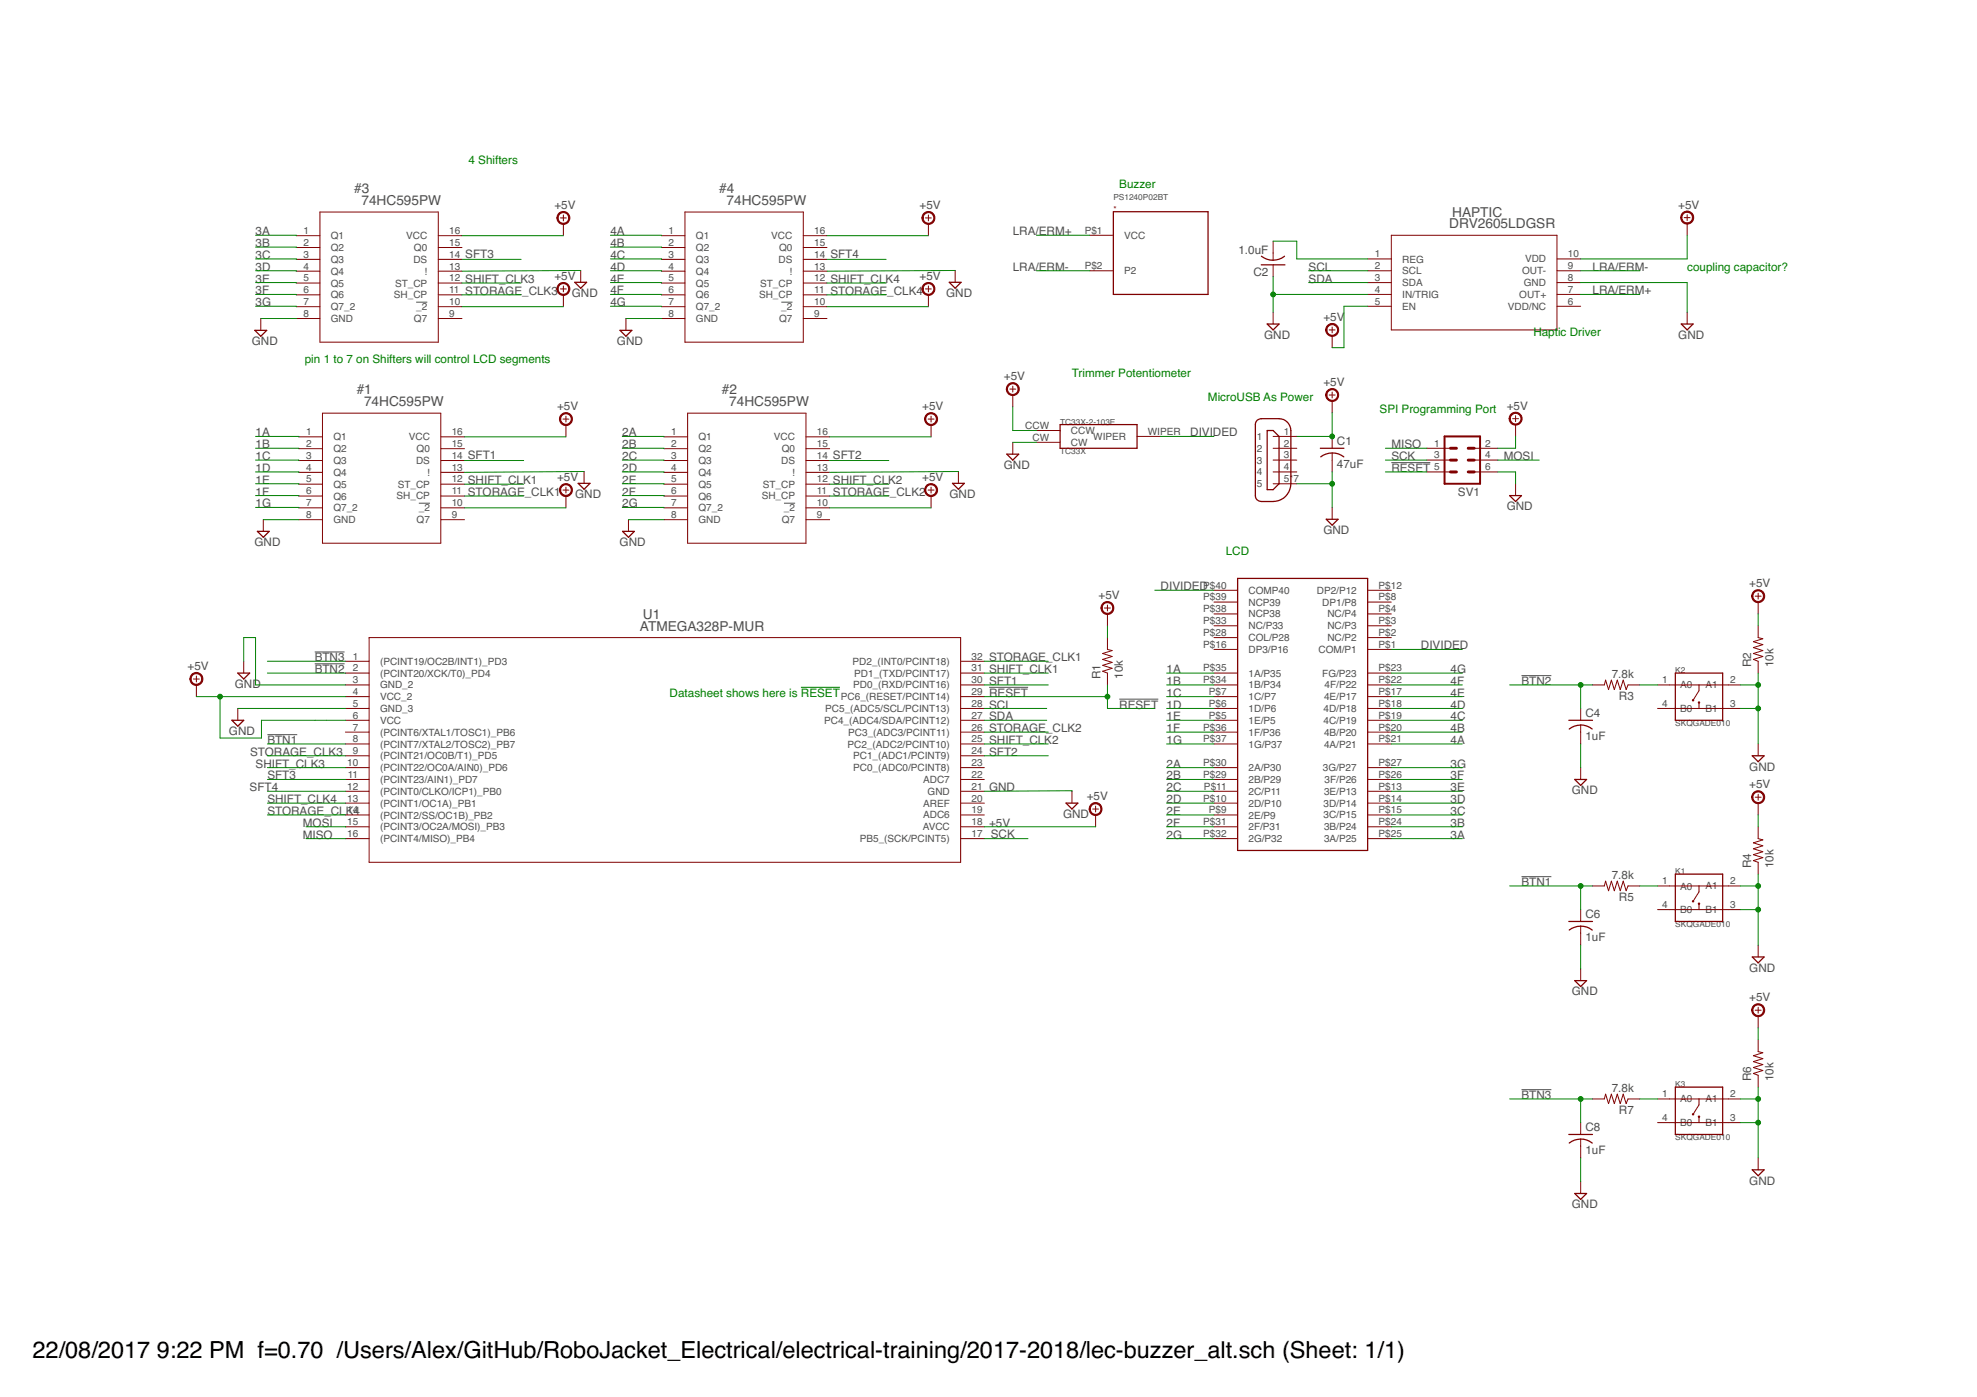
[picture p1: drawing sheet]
<svg xmlns="http://www.w3.org/2000/svg" width="297mm" height="210mm" viewBox="0 0 297 210" stroke-linecap="round" stroke-linejoin="round" font-family="sans-serif">
<defs><g id="words">
<g font-size="3.5">
<text x="4.9" y="204">22/08/2017</text>
<text x="23.6" y="204">9:22 PM f=0.70 /Users/Alex/GitHub/RoboJacket_Electrical/electrical-training/2017-2018/lec-buzzer_alt.sch (Sheet: 1/1)</text>
</g>
<g font-size="2.1" fill="#505050">
<text x="53.2" y="29">#3</text>
<text x="108.1" y="29">#4</text>
<text x="54.3" y="30.8">74HC595PW</text>
<text x="109.2" y="30.8">74HC595PW</text>
<text x="217.7" y="34.3">DRV2605LDGSR</text>
<text x="218.2" y="32.5">HAPTIC</text>
<text x="53.6" y="59.3">#1</text>
<text x="108.5" y="59.3">#2</text>
<text x="54.7" y="61">74HC595PW</text>
<text x="109.6" y="61">74HC595PW</text>
<text x="96.2" y="94.7">ATMEGA328P-MUR</text>
<text x="96.6" y="93">U1</text>
</g>
<g font-size="1.8" fill="#008000">
<text x="70.4" y="24.7">4 Shifters</text>
<text x="168.2" y="28.2">Buzzer</text>
<text x="253.5" y="40.7">coupling capacitor?</text>
<text x="230.4" y="50.5">Haptic Driver</text>
<text x="45.8" y="54.6">pin 1 to 7 on Shifters will control LCD segments</text>
<text x="161.1" y="56.7">Trimmer Potentiometer</text>
<text x="181.5" y="60.2">MicroUSB As Power</text>
<text x="207.3" y="62">SPI Programming Port</text>
<text x="184.2" y="83.3">LCD</text>
<text x="100.6" y="104.7">Datasheet shows here is RESET</text>
</g>
<g font-size="1.8" fill="#505050">
<text x="38.4" y="35.4">3A</text>
<text x="83.3" y="31.4">+5V</text>
<text x="91.7" y="35.4">4A</text>
<text x="138.2" y="31.4">+5V</text>
<text x="152.2" y="35.4">LRA/ERM+</text>
<text x="252.2" y="31.4">+5V</text>
<text x="38.4" y="37.1">3B</text>
<text x="38.4" y="38.9">3C</text>
<text x="38.4" y="40.7">3D</text>
<text x="69.9" y="38.7">SFT3</text>
<text x="91.7" y="37.1">4B</text>
<text x="91.7" y="38.9">4C</text>
<text x="91.7" y="40.7">4D</text>
<text x="124.8" y="38.7">SFT4</text>
<text x="152.2" y="40.7">LRA/ERM-</text>
<text x="186.1" y="38.1">1.0uF</text>
<text x="188.3" y="41.5">C2</text>
<text x="196.6" y="40.7">SCL</text>
<text x="239.3" y="40.7">LRA/ERM-</text>
<text x="38.4" y="42.5">3E</text>
<text x="38.4" y="44.2">3F</text>
<text x="38.4" y="46">3G</text>
<text x="69.9" y="44.3">STORAGE_CLK3</text>
<text x="69.9" y="42.6">SHIFT_CLK3</text>
<text x="83.3" y="42.1">+5V</text>
<text x="85.9" y="44.6">GND</text>
<text x="91.7" y="42.5">4E</text>
<text x="91.7" y="44.2">4F</text>
<text x="91.7" y="46">4G</text>
<text x="124.8" y="42.6">SHIFT_CLK4</text>
<text x="124.8" y="44.3">STORAGE_CLK4</text>
<text x="138.2" y="42.1">+5V</text>
<text x="142.2" y="44.6">GND</text>
<text x="196.6" y="42.5">SDA</text>
<text x="239.3" y="44.2">LRA/ERM+</text>
<text x="37.8" y="51.9">GND</text>
<text x="92.7" y="51.9">GND</text>
<text x="189.9" y="50.9">GND</text>
<text x="198.8" y="48.2">+5V</text>
<text x="252.2" y="50.9">GND</text>
<text x="150.8" y="57.1">+5V</text>
<text x="198.8" y="58">+5V</text>
<text x="38.4" y="65.6">1A</text>
<text x="83.7" y="61.6">+5V</text>
<text x="93.5" y="65.6">2A</text>
<text x="138.6" y="61.6">+5V</text>
<text x="178.8" y="65.6">DIVIDED</text>
<text x="226.4" y="61.6">+5V</text>
<text x="38.4" y="67.4">1B</text>
<text x="38.4" y="69.1">1C</text>
<text x="38.4" y="70.9">1D</text>
<text x="70.3" y="68.9">SFT1</text>
<text x="93.5" y="67.4">2B</text>
<text x="93.5" y="69.1">2C</text>
<text x="93.5" y="70.9">2D</text>
<text x="125.2" y="68.9">SFT2</text>
<text x="150.8" y="70.5">GND</text>
<text x="200.9" y="70.3">47uF</text>
<text x="200.9" y="66.9">C1</text>
<text x="209.1" y="67.4">MISO</text>
<text x="209.1" y="69.1">SCK</text>
<text x="209.1" y="70.9">RESET</text>
<text x="225.9" y="69.1">MOSI</text>
<text x="38.4" y="72.7">1E</text>
<text x="38.4" y="74.5">1F</text>
<text x="38.4" y="76.2">1G</text>
<text x="70.3" y="72.8">SHIFT_CLK1</text>
<text x="70.3" y="74.5">STORAGE_CLK1</text>
<text x="83.7" y="72.3">+5V</text>
<text x="86.4" y="74.9">GND</text>
<text x="93.5" y="72.7">2E</text>
<text x="93.5" y="74.5">2F</text>
<text x="93.5" y="76.2">2G</text>
<text x="125.2" y="74.5">STORAGE_CLK2</text>
<text x="125.2" y="72.8">SHIFT_CLK2</text>
<text x="138.6" y="72.3">+5V</text>
<text x="142.7" y="74.9">GND</text>
<text x="219.1" y="74.5">SV1</text>
<text x="226.4" y="76.7">GND</text>
<text x="38.2" y="82.1">GND</text>
<text x="93.1" y="82.1">GND</text>
<text x="198.8" y="80.2">GND</text>
<text x="174.4" y="88.7">DIVIDED</text>
<text x="262.8" y="88.2">+5V</text>
<text x="165.1" y="90">+5V</text>
<text x="28.2" y="100.7">+5V</text>
<text x="47.3" y="99.3">BTN3</text>
<text x="47.3" y="101.1">BTN2</text>
<text x="148.6" y="101.1">SHIFT_CLK1</text>
<text x="148.6" y="99.3">STORAGE_CLK1</text>
<text x="175.3" y="101.1">1A</text>
<text x="213.5" y="97.6">DIVIDED</text>
<text x="217.9" y="101.1">4G</text>
<text x="242.2" y="101.8">7.8k</text>
<text x="263.1" y="100.2" transform="rotate(-90 263.1 100.2)">R2</text>
<text x="266.5" y="100.2" transform="rotate(-90 266.5 100.2)">10k</text>
<text x="35.3" y="103.3">GND</text>
<text x="148.6" y="102.9">SFT1</text>
<text x="148.6" y="104.7">RESET</text>
<text x="148.6" y="106.5">SCL</text>
<text x="165.3" y="102" transform="rotate(-90 165.3 102)">R1</text>
<text x="168.2" y="106.5">RESET</text>
<text x="168.7" y="102" transform="rotate(-90 168.7 102)">10k</text>
<text x="175.3" y="102.9">1B</text>
<text x="175.3" y="104.7">1C</text>
<text x="175.3" y="106.5">1D</text>
<text x="217.9" y="106.5">4D</text>
<text x="217.9" y="104.7">4E</text>
<text x="217.9" y="102.9">4F</text>
<text x="228.6" y="102.9">BTN2</text>
<text x="238.2" y="107.8">C4</text>
<text x="243.2" y="105.2">R3</text>
<text x="34.4" y="110.5">GND</text>
<text x="37.6" y="113.6">STORAGE_CLK3</text>
<text x="40.2" y="111.8">BTN1</text>
<text x="148.6" y="113.6">SFT2</text>
<text x="148.6" y="108.2">SDA</text>
<text x="148.6" y="110">STORAGE_CLK2</text>
<text x="148.6" y="111.8">SHIFT_CLK2</text>
<text x="175.3" y="108.2">1E</text>
<text x="175.3" y="110">1F</text>
<text x="175.3" y="111.8">1G</text>
<text x="217.9" y="111.8">4A</text>
<text x="217.9" y="110">4B</text>
<text x="217.9" y="108.2">4C</text>
<text x="238.2" y="111.2">1uF</text>
<text x="37.5" y="118.9">SFT4</text>
<text x="38.4" y="115.3">SHIFT_CLK3</text>
<text x="40.2" y="117.1">SFT3</text>
<text x="148.6" y="118.9">GND</text>
<text x="175.3" y="115.3">2A</text>
<text x="175.3" y="117.1">2B</text>
<text x="175.3" y="118.9">2C</text>
<text x="217.9" y="118.9">3E</text>
<text x="217.9" y="117.1">3F</text>
<text x="217.9" y="115.3">3G</text>
<text x="236.2" y="119.3">GND</text>
<text x="262.8" y="115.8">GND</text>
<text x="262.8" y="118.5">+5V</text>
<text x="40.2" y="120.7">SHIFT_CLK4</text>
<text x="40.2" y="122.5">STORAGE_CLK4</text>
<text x="45.5" y="124.2">MOSI</text>
<text x="148.6" y="124.2">+5V</text>
<text x="148.9" y="125.9">SCK</text>
<text x="159.7" y="122.9">GND</text>
<text x="163.3" y="120.2">+5V</text>
<text x="175.3" y="120.7">2D</text>
<text x="175.3" y="122.5">2E</text>
<text x="175.3" y="124.2">2F</text>
<text x="217.9" y="124.2">3B</text>
<text x="217.9" y="122.5">3C</text>
<text x="217.9" y="120.7">3D</text>
<text x="45.5" y="126">MISO</text>
<text x="175.3" y="126">2G</text>
<text x="217.9" y="126">3A</text>
<text x="263.1" y="130.5" transform="rotate(-90 263.1 130.5)">R4</text>
<text x="266.5" y="130.5" transform="rotate(-90 266.5 130.5)">10k</text>
<text x="228.6" y="133.1">BTN1</text>
<text x="242.2" y="132.1">7.8k</text>
<text x="243.2" y="135.4">R5</text>
<text x="238.2" y="141.4">1uF</text>
<text x="238.2" y="138">C6</text>
<text x="236.2" y="149.6">GND</text>
<text x="262.8" y="146">GND</text>
<text x="262.8" y="150.4">+5V</text>
<text x="228.6" y="165.1">BTN3</text>
<text x="242.2" y="164.1">7.8k</text>
<text x="243.2" y="167.4">R7</text>
<text x="263.1" y="162.4" transform="rotate(-90 263.1 162.4)">R6</text>
<text x="266.5" y="162.4" transform="rotate(-90 266.5 162.4)">10k</text>
<text x="238.2" y="173.4">1uF</text>
<text x="238.2" y="170">C8</text>
<text x="262.8" y="178">GND</text>
<text x="236.2" y="181.6">GND</text>
</g>
<g font-size="1.5" fill="#505050">
<text x="45.6" y="35.2">1</text>
<text x="49.7" y="35.9">Q1</text>
<text x="61" y="35.9">VCC</text>
<text x="67.5" y="35.2">16</text>
<text x="100.5" y="35.2">1</text>
<text x="104.6" y="35.9">Q1</text>
<text x="115.9" y="35.9">VCC</text>
<text x="122.3" y="35.2">16</text>
<text x="163" y="35.1">P$1</text>
<text x="168.9" y="35.9">VCC</text>
<text x="45.6" y="36.9">2</text>
<text x="45.6" y="38.7">3</text>
<text x="45.6" y="40.5">4</text>
<text x="49.7" y="37.7">Q2</text>
<text x="49.7" y="39.5">Q3</text>
<text x="49.7" y="41.3">Q4</text>
<text x="62.1" y="39.5">DS</text>
<text x="62.2" y="37.7">Q0</text>
<text x="63.8" y="41.3">!</text>
<text x="67.5" y="40.5">13</text>
<text x="67.5" y="38.7">14</text>
<text x="67.5" y="36.9">15</text>
<text x="100.5" y="36.9">2</text>
<text x="100.5" y="38.7">3</text>
<text x="100.5" y="40.5">4</text>
<text x="104.6" y="37.7">Q2</text>
<text x="104.6" y="39.5">Q3</text>
<text x="104.6" y="41.3">Q4</text>
<text x="117" y="39.5">DS</text>
<text x="117.1" y="37.7">Q0</text>
<text x="118.6" y="41.3">!</text>
<text x="122.3" y="40.5">13</text>
<text x="122.3" y="38.7">14</text>
<text x="122.3" y="36.9">15</text>
<text x="163" y="40.4">P$2</text>
<text x="168.9" y="41.2">P2</text>
<text x="206.6" y="38.7">1</text>
<text x="206.6" y="40.4">2</text>
<text x="210.7" y="39.4">REG</text>
<text x="210.7" y="41.2">SCL</text>
<text x="228.7" y="41.2">OUT-</text>
<text x="229.1" y="39.4">VDD</text>
<text x="235.6" y="40.4">9</text>
<text x="235.6" y="38.7">10</text>
<text x="45.6" y="42.3">5</text>
<text x="45.6" y="44.1">6</text>
<text x="45.6" y="45.8">7</text>
<text x="45.6" y="47.6">8</text>
<text x="49.7" y="43.1">Q5</text>
<text x="49.7" y="44.8">Q6</text>
<text x="49.7" y="46.6">Q7_2</text>
<text x="59.2" y="44.8">SH_CP</text>
<text x="59.4" y="43">ST_CP</text>
<text x="62.5" y="46.6">_2</text>
<text x="67.5" y="47.6">9</text>
<text x="67.5" y="45.8">10</text>
<text x="67.5" y="44.1">11</text>
<text x="67.5" y="42.3">12</text>
<text x="100.5" y="42.3">5</text>
<text x="100.5" y="44.1">6</text>
<text x="100.5" y="45.8">7</text>
<text x="100.5" y="47.6">8</text>
<text x="104.6" y="43.1">Q5</text>
<text x="104.6" y="44.8">Q6</text>
<text x="104.6" y="46.6">Q7_2</text>
<text x="114" y="44.8">SH_CP</text>
<text x="114.2" y="43">ST_CP</text>
<text x="117.4" y="46.6">_2</text>
<text x="122.3" y="47.6">9</text>
<text x="122.3" y="45.8">10</text>
<text x="122.3" y="44.1">11</text>
<text x="122.3" y="42.3">12</text>
<text x="206.6" y="42.2">3</text>
<text x="206.6" y="44">4</text>
<text x="206.6" y="45.8">5</text>
<text x="210.7" y="43">SDA</text>
<text x="210.7" y="44.8">IN/TRIG</text>
<text x="210.7" y="46.6">EN</text>
<text x="226.5" y="46.5">VDD/NC</text>
<text x="228.3" y="44.8">OUT+</text>
<text x="229" y="43">GND</text>
<text x="235.6" y="45.8">6</text>
<text x="235.6" y="44">7</text>
<text x="235.6" y="42.2">8</text>
<text x="49.7" y="48.4">GND</text>
<text x="62.2" y="48.4">Q7</text>
<text x="104.6" y="48.4">GND</text>
<text x="117.1" y="48.4">Q7</text>
<text x="46" y="65.4">1</text>
<text x="67.9" y="65.4">16</text>
<text x="100.9" y="65.4">1</text>
<text x="122.7" y="65.4">16</text>
<text x="154" y="64.4">CCW</text>
<text x="160.9" y="65.2">CCW</text>
<text x="172.5" y="65.3">WIPER</text>
<text x="192.9" y="65.3">1</text>
<text x="46" y="67.2">2</text>
<text x="46" y="68.9">3</text>
<text x="46" y="70.7">4</text>
<text x="50.1" y="66.2">Q1</text>
<text x="50.1" y="67.9">Q2</text>
<text x="50.1" y="69.7">Q3</text>
<text x="50.1" y="71.5">Q4</text>
<text x="61.4" y="66.2">VCC</text>
<text x="62.5" y="69.7">DS</text>
<text x="62.6" y="67.9">Q0</text>
<text x="64.2" y="71.5">!</text>
<text x="67.9" y="70.7">13</text>
<text x="67.9" y="68.9">14</text>
<text x="67.9" y="67.2">15</text>
<text x="100.9" y="67.2">2</text>
<text x="100.9" y="68.9">3</text>
<text x="100.9" y="70.7">4</text>
<text x="105" y="66.2">Q1</text>
<text x="105" y="67.9">Q2</text>
<text x="105" y="69.7">Q3</text>
<text x="105" y="71.5">Q4</text>
<text x="116.3" y="66.2">VCC</text>
<text x="117.4" y="69.7">DS</text>
<text x="117.4" y="67.9">Q0</text>
<text x="119" y="71.5">!</text>
<text x="122.7" y="70.7">13</text>
<text x="122.7" y="68.9">14</text>
<text x="122.7" y="67.2">15</text>
<text x="155.1" y="66.2">CW</text>
<text x="160.9" y="67">CW</text>
<text x="164.3" y="66.1">WIPER</text>
<text x="188.8" y="66.1">1</text>
<text x="188.8" y="67.9">2</text>
<text x="188.8" y="69.7">3</text>
<text x="188.8" y="71.4">4</text>
<text x="192.9" y="67.1">2</text>
<text x="192.9" y="68.9">3</text>
<text x="192.9" y="70.7">4</text>
<text x="215.5" y="67.1">1</text>
<text x="215.5" y="68.9">3</text>
<text x="215.5" y="70.7">5</text>
<text x="223.1" y="67.1">2</text>
<text x="223.1" y="68.9">4</text>
<text x="223.1" y="70.7">6</text>
<text x="46" y="72.5">5</text>
<text x="46" y="74.3">6</text>
<text x="46" y="76">7</text>
<text x="46" y="77.8">8</text>
<text x="50.1" y="73.3">Q5</text>
<text x="50.1" y="75.1">Q6</text>
<text x="50.1" y="76.8">Q7_2</text>
<text x="59.6" y="75">SH_CP</text>
<text x="59.8" y="73.3">ST_CP</text>
<text x="62.9" y="76.8">_2</text>
<text x="67.9" y="77.8">9</text>
<text x="67.9" y="76">10</text>
<text x="67.9" y="74.3">11</text>
<text x="67.9" y="72.5">12</text>
<text x="100.9" y="72.5">5</text>
<text x="100.9" y="74.3">6</text>
<text x="100.9" y="76">7</text>
<text x="100.9" y="77.8">8</text>
<text x="105" y="73.3">Q5</text>
<text x="105" y="75.1">Q6</text>
<text x="105" y="76.8">Q7_2</text>
<text x="114.4" y="75">SH_CP</text>
<text x="114.6" y="73.3">ST_CP</text>
<text x="117.8" y="76.8">_2</text>
<text x="122.7" y="77.8">9</text>
<text x="122.7" y="76">10</text>
<text x="122.7" y="74.3">11</text>
<text x="122.7" y="72.5">12</text>
<text x="188.8" y="73.2">5</text>
<text x="192.9" y="72.4">5*</text>
<text x="194.3" y="72.4">7</text>
<text x="50.1" y="78.6">GND</text>
<text x="62.6" y="78.6">Q7</text>
<text x="105" y="78.6">GND</text>
<text x="117.4" y="78.6">Q7</text>
<text x="180.8" y="88.4">P$40</text>
<text x="187.6" y="89.2">COMP40</text>
<text x="197.8" y="89.2">DP2/P12</text>
<text x="207.1" y="88.4">P$12</text>
<text x="180.8" y="90.2">P$39</text>
<text x="180.8" y="92">P$38</text>
<text x="180.8" y="93.8">P$33</text>
<text x="180.8" y="95.5">P$28</text>
<text x="187.6" y="91">NCP39</text>
<text x="187.6" y="92.8">NCP38</text>
<text x="187.6" y="94.5">NC/P33</text>
<text x="198.7" y="91">DP1/P8</text>
<text x="199.4" y="94.5">NC/P3</text>
<text x="199.4" y="92.8">NC/P4</text>
<text x="207.1" y="95.5">P$2</text>
<text x="207.1" y="93.8">P$3</text>
<text x="207.1" y="92">P$4</text>
<text x="207.1" y="90.2">P$8</text>
<text x="53" y="99.1">1</text>
<text x="53" y="100.9">2</text>
<text x="57.1" y="99.9">(PCINT19/OC2B/INT1)_PD3</text>
<text x="57.1" y="101.7">(PCINT20/XCK/T0)_PD4</text>
<text x="128.1" y="99.9">PD2_(INT0/PCINT18)</text>
<text x="128.4" y="101.6">PD1_(TXD/PCINT17)</text>
<text x="146" y="100.9">31</text>
<text x="146" y="99.1">32</text>
<text x="180.8" y="100.9">P$35</text>
<text x="180.8" y="97.3">P$16</text>
<text x="187.6" y="101.7">1A/P35</text>
<text x="187.6" y="96.3">COL/P28</text>
<text x="187.6" y="98.1">DP3/P16</text>
<text x="198.1" y="98.1">COM/P1</text>
<text x="198.7" y="101.6">FG/P23</text>
<text x="199.4" y="96.3">NC/P2</text>
<text x="207.1" y="100.9">P$23</text>
<text x="207.1" y="97.3">P$1</text>
<text x="53" y="102.7">3</text>
<text x="53" y="104.4">4</text>
<text x="53" y="106.2">5</text>
<text x="53" y="108">6</text>
<text x="57.1" y="103.4">GND_2</text>
<text x="57.1" y="105.2">VCC_2</text>
<text x="57.1" y="107">GND_3</text>
<text x="124" y="107">PC5_(ADC5/SCL/PCINT13)</text>
<text x="126.3" y="105.2">PC6_(RESET/PCINT14)</text>
<text x="128.2" y="103.4">PD0_(RXD/PCINT16)</text>
<text x="146" y="108">27</text>
<text x="146" y="106.2">28</text>
<text x="146" y="104.4">29</text>
<text x="146" y="102.7">30</text>
<text x="180.8" y="102.7">P$34</text>
<text x="181.6" y="104.4">P$7</text>
<text x="181.6" y="106.2">P$6</text>
<text x="181.6" y="108">P$5</text>
<text x="187.6" y="103.4">1B/P34</text>
<text x="187.6" y="105.2">1C/P7</text>
<text x="187.6" y="107">1D/P6</text>
<text x="198.8" y="107">4D/P18</text>
<text x="198.9" y="105.2">4E/P17</text>
<text x="199" y="103.4">4F/P22</text>
<text x="207.1" y="108">P$19</text>
<text x="207.1" y="106.2">P$18</text>
<text x="207.1" y="104.4">P$17</text>
<text x="207.1" y="102.7">P$22</text>
<text x="249.8" y="102.7">1</text>
<text x="249.8" y="106.2">4</text>
<text x="252.5" y="103.4">A0</text>
<text x="252.5" y="107">B0</text>
<text x="256.2" y="103.4">A1</text>
<text x="256.2" y="107">B1</text>
<text x="260" y="102.7">2</text>
<text x="260" y="106.2">3</text>
<text x="53" y="109.8">7</text>
<text x="53" y="111.5">8</text>
<text x="53" y="113.3">9</text>
<text x="57.1" y="108.8">VCC</text>
<text x="57.1" y="110.5">(PCINT6/XTAL1/TOSC1)_PB6</text>
<text x="57.1" y="112.3">(PCINT7/XTAL2/TOSC2)_PB7</text>
<text x="123.8" y="108.8">PC4_(ADC4/SDA/PCINT12)</text>
<text x="127.3" y="112.3">PC2_(ADC2/PCINT10)</text>
<text x="127.4" y="110.5">PC3_(ADC3/PCINT11)</text>
<text x="146" y="113.3">24</text>
<text x="146" y="111.5">25</text>
<text x="146" y="109.8">26</text>
<text x="180.8" y="109.8">P$36</text>
<text x="180.8" y="111.5">P$37</text>
<text x="187.6" y="108.8">1E/P5</text>
<text x="187.6" y="110.5">1F/P36</text>
<text x="187.6" y="112.3">1G/P37</text>
<text x="198.8" y="108.8">4C/P19</text>
<text x="198.9" y="112.3">4A/P21</text>
<text x="198.9" y="110.5">4B/P20</text>
<text x="207.1" y="111.5">P$21</text>
<text x="207.1" y="109.8">P$20</text>
<text x="52.2" y="115.1">10</text>
<text x="52.2" y="118.7">12</text>
<text x="52.3" y="116.9">11</text>
<text x="57.1" y="114.1">(PCINT21/OC0B/T1)_PD5</text>
<text x="57.1" y="115.9">(PCINT22/OC0A/AIN0)_PD6</text>
<text x="57.1" y="117.7">(PCINT23/AIN1)_PD7</text>
<text x="57.1" y="119.4">(PCINT0/CLKO/ICP1)_PB0</text>
<text x="128.2" y="115.9">PC0_(ADC0/PCINT8)</text>
<text x="128.2" y="114.1">PC1_(ADC1/PCINT9)</text>
<text x="138.7" y="117.6">ADC7</text>
<text x="139.4" y="119.4">GND</text>
<text x="146" y="118.7">21</text>
<text x="146" y="116.9">22</text>
<text x="146" y="115.1">23</text>
<text x="180.8" y="115.1">P$30</text>
<text x="180.8" y="116.9">P$29</text>
<text x="180.9" y="118.7">P$11</text>
<text x="187.6" y="115.9">2A/P30</text>
<text x="187.6" y="117.7">2B/P29</text>
<text x="187.6" y="119.4">2C/P11</text>
<text x="198.8" y="115.9">3G/P27</text>
<text x="198.9" y="119.4">3E/P13</text>
<text x="199" y="117.6">3F/P26</text>
<text x="207.1" y="118.7">P$13</text>
<text x="207.1" y="116.9">P$26</text>
<text x="207.1" y="115.1">P$27</text>
<text x="52.2" y="120.4">13</text>
<text x="52.2" y="122.2">14</text>
<text x="52.2" y="124">15</text>
<text x="52.2" y="125.8">16</text>
<text x="57.1" y="121.2">(PCINT1/OC1A)_PB1</text>
<text x="57.1" y="123">(PCINT2/SS/OC1B)_PB2</text>
<text x="57.1" y="124.8">(PCINT3/OC2A/MOSI)_PB3</text>
<text x="138.6" y="124.8">AVCC</text>
<text x="138.7" y="123">ADC6</text>
<text x="138.7" y="121.2">AREF</text>
<text x="146" y="125.8">17</text>
<text x="146" y="124">18</text>
<text x="146" y="122.2">19</text>
<text x="146" y="120.4">20</text>
<text x="180.8" y="120.4">P$10</text>
<text x="180.8" y="124">P$31</text>
<text x="180.8" y="125.8">P$32</text>
<text x="181.6" y="122.2">P$9</text>
<text x="187.6" y="121.2">2D/P10</text>
<text x="187.6" y="123">2E/P9</text>
<text x="187.6" y="124.8">2F/P31</text>
<text x="198.8" y="123">3C/P15</text>
<text x="198.8" y="121.2">3D/P14</text>
<text x="198.9" y="124.8">3B/P24</text>
<text x="207.1" y="125.8">P$25</text>
<text x="207.1" y="124">P$24</text>
<text x="207.1" y="122.2">P$15</text>
<text x="207.1" y="120.4">P$14</text>
<text x="57.1" y="126.5">(PCINT4/MISO)_PB4</text>
<text x="129.2" y="126.5">PB5_(SCK/PCINT5)</text>
<text x="187.6" y="126.5">2G/P32</text>
<text x="198.9" y="126.5">3A/P25</text>
<text x="249.8" y="132.9">1</text>
<text x="249.8" y="136.4">4</text>
<text x="252.5" y="133.7">A0</text>
<text x="252.5" y="137.2">B0</text>
<text x="256.2" y="133.6">A1</text>
<text x="256.2" y="137.2">B1</text>
<text x="260" y="132.9">2</text>
<text x="260" y="136.4">3</text>
<text x="249.8" y="164.9">1</text>
<text x="252.5" y="165.6">A0</text>
<text x="256.2" y="165.6">A1</text>
<text x="260" y="164.9">2</text>
<text x="249.8" y="168.4">4</text>
<text x="252.5" y="169.2">B0</text>
<text x="256.2" y="169.2">B1</text>
<text x="260" y="168.4">3</text>
</g>
<g font-size="1.2" fill="#505050">
<text x="167.3" y="30">PS1240P02BT</text>
<text x="159.3" y="63.8">TC33X-2-103E</text>
<text x="159.3" y="68.2">TC33X</text>
<text x="251.7" y="101.1">K2</text>
<text x="251.7" y="109.1">SKQGADE010</text>
<text x="251.7" y="131.3">K1</text>
<text x="251.7" y="139.3">SKQGADE010</text>
<text x="251.7" y="163.3">K3</text>
<text x="251.7" y="171.3">SKQGADE010</text>
</g>
<text font-size="1.2" fill="#800000" x="167.3" y="31.8">*</text>
</g></defs>
<g fill="none" stroke="#505050" stroke-width=".15">
<path d="M62.5 45.4h1.7M117.4 45.4h1.7M62.9 75.6h1.7M117.8 75.6h1.7M209 69.5h5.9M47.3 98h4.5M47.3 99.7h4.5M40.2 110.4h4.5M148.6 103.3h5.9M168.2 105.1h5.8M228.6 101.5h4.5M228.6 131.7h4.5"/>
<path d="M228.6 163.7h4.5"/>
</g>
<g fill="none" stroke="#800000" stroke-width=".15">
<path d="M44.5 35.4h3.6M44.5 37.2h3.6M44.5 39h3.6M48.1 31.9h17.7v19.5h-17.7zM65.8 35.4h3.6M65.8 37.2h3.6M65.8 39h3.6M84.2 32.7h.9M84.6 32.3v.9M84.6 33.6v1.8M99.4 35.4h3.5M99.4 37.2h3.5"/>
<path d="M99.4 39h3.5M102.9 31.9h17.8v19.5h-17.8zM120.7 35.4h3.5M120.7 37.2h3.5M120.7 39h3.5M139 32.7h.9M139.5 32.3v.9M139.5 33.6v1.8M163.7 35.3h3.6M191.3 36.2v2.9M191.3 39.8v1.8M205.5 38.9h3.5"/>
<path d="M209 35.3h24.9v14.3h-24.9zM233.9 38.9h3.6M253 32.7h.9M253.5 32.3v.8M253.5 33.6v1.7M39.2 47.9v1.7M44.5 40.7h3.6M44.5 42.5h3.6M44.5 44.3h3.6M44.5 46.1h3.6M44.5 47.9h3.6M65.8 40.7h3.6"/>
<path d="M65.8 42.5h3.6M65.8 44.3h3.6M65.8 46.1h3.6M65.8 47.9h3.6M84.2 43.4h.9M84.6 43v.9M84.6 44.3v1.8M87.2 40.6v1.8M94 47.9v1.7M99.4 40.7h3.5M99.4 42.5h3.5M99.4 44.3h3.5"/>
<path d="M99.4 46.1h3.5M99.4 47.9h3.5M120.7 40.7h3.5M120.7 42.5h3.5M120.7 44.3h3.5M120.7 46.1h3.5M120.7 47.9h3.5M139 43.4h.9M139.5 43v.9M139.5 44.3v1.8M143.5 40.6v1.8M151.7 58.5h.9"/>
<path d="M152.2 58v.9M152.2 59.4v1.7M163.7 40.7h3.6M191.3 46.9v1.8M199.7 59.4h.9M199.7 49.6h.9M200.2 49.1v.9M200.2 50.5v1.7M200.2 58.9v.9M205.5 40.7h3.5M205.5 42.5h3.5M205.5 44.2h3.5"/>
<path d="M205.5 46h3.5M233.9 40.7h3.6M233.9 42.5h3.6M233.9 44.2h3.6M233.9 46h3.6M253.5 46.9v1.8M39.6 78.1v1.7M44.9 65.6h3.6M44.9 67.4h3.6M44.9 69.2h3.6M44.9 71h3.6M44.9 72.7h3.6"/>
<path d="M44.9 74.5h3.6M44.9 76.3h3.6M44.9 78.1h3.6M48.5 62.1h17.7v19.5h-17.7zM66.2 65.6h3.6M66.2 67.4h3.6M66.2 69.2h3.6M66.2 71h3.6M66.2 72.7h3.6M66.2 74.5h3.6M66.2 76.3h3.6M66.2 78.1h3.6"/>
<path d="M84.6 63h.9M84.6 73.6h.9M85 62.5v.9M85 63.9v1.7M85 73.2v.9M85 74.5v1.8M87.8 70.8v1.8M94.4 78.1v1.7M99.8 65.6h3.5M99.8 67.4h3.5M99.8 69.2h3.5M99.8 71h3.5"/>
<path d="M99.8 72.7h3.5M99.8 74.5h3.5M99.8 76.3h3.5M99.8 78.1h3.5M103.3 62.1h17.8v19.5h-17.8zM121.1 65.6h3.6M121.1 67.4h3.6M121.1 69.2h3.6M121.1 71h3.6M121.1 72.7h3.6M121.1 74.5h3.6M121.1 76.3h3.6"/>
<path d="M121.1 78.1h3.6M139.4 63h.9M139.4 73.6h.9M139.9 62.5v.9M139.9 63.9v1.7M139.9 73.2v.9M139.9 74.5v1.8M144 70.8v1.8M152.2 66.5v1.7M155.7 64.7h3.6M155.7 66.5h3.6M170.8 65.6h3.6"/>
<path d="M191.3 65.6h3.5M191.3 67.4h3.5M191.3 69.1h3.5M191.3 70.9h3.5M191.3 72.7h3.5M200.2 60.2v1.8M200.2 65.6v1.8M200.2 68.1v2.8M200.2 76.2v1.8M214.4 67.4h3.5M214.4 69.1h3.5M214.4 70.9h3.5"/>
<path d="M221.5 67.4h3.5M221.5 69.1h3.5M221.5 70.9h3.5M227.3 62.9h.9M227.7 62.5v.9M227.7 63.8v1.8M227.7 72.7v1.8M36.6 99.4v1.7M51.9 99.4h3.6M55.5 95.8h88.8v33.8h-88.8zM144.3 99.4h3.6M165.9 91.4h.9"/>
<path d="M166.4 95.8v1.8l.7 .1-1.4 .5 1.4 .4-1.4 .5 1.4 .4-1.4 .5 1.4 .4-1.4 .5 .7 .2v1.8M166.4 90.9v.9M166.4 92.2v1.8M182.4 95.8h3.5M182.4 97.6h3.5M182.4 94h3.5M182.4 92.2h3.5M182.4 90.5h3.5M182.4 88.7h3.5M205.5 95.8h3.5M205.5 97.6h3.5M205.5 94h3.5"/>
<path d="M205.5 92.2h3.5M205.5 90.5h3.5M205.5 88.7h3.5M263.7 89.6h.9M264.2 89.1v.9M264.2 90.5v1.7M264.2 94v1.8l.7 .2-1.5 .4 1.5 .5-1.5 .4 1.5 .4-1.5 .5 1.5 .4-1.5 .5 .8 .3v1.7M29.1 102h.9M29.5 101.6v.9M29.5 102.9v1.8M35.7 106.4v1.8M51.9 101.1h3.6"/>
<path d="M51.9 102.9h3.6M51.9 104.7h3.6M51.9 106.4h3.6M51.9 108.2h3.6M51.9 110h3.6M51.9 111.8h3.6M51.9 113.6h3.6M51.9 115.3h3.6M51.9 117.1h3.6M51.9 118.9h3.6M144.3 101.1h3.6M144.3 102.9h3.6"/>
<path d="M144.3 104.7h3.6M144.3 106.4h3.6M144.3 108.2h3.6M144.3 110h3.6M144.3 111.8h3.6M144.3 113.6h3.6M144.3 115.3h3.6M144.3 117.1h3.6M144.3 118.9h3.6M161.1 118.9v1.8M182.4 101.1h3.5M182.4 102.9h3.5"/>
<path d="M182.4 104.7h3.5M182.4 106.4h3.5M182.4 108.2h3.5M182.4 110h3.5M182.4 111.8h3.5M182.4 115.3h3.5M182.4 117.1h3.5M182.4 118.9h3.5M205.5 101.1h3.5M205.5 102.9h3.5M205.5 104.7h3.5M205.5 106.4h3.5"/>
<path d="M205.5 108.2h3.5M205.5 110h3.5M205.5 111.8h3.5M205.5 115.3h3.5M205.5 117.1h3.5M205.5 118.9h3.5M237.5 106.4v1.8M237.5 108.9v2.9M237.5 115.3v1.8M239.3 102.9h1.7l.2-.7 .5 1.4 .4-1.4 .4 1.4 .5-1.4 .4 1.4 .5-1.4 .4 1.4 .3-.7h1.8M249 102.9h12.5M249 106.4h12.5"/>
<path d="M255.3 102.9v.9l-.9 1.4M255.3 105.6v.8M263.7 119.8h.9M264.2 111.8v1.8M264.2 119.3v.9M51.9 120.7h3.6M51.9 122.4h3.6M51.9 124.2h3.6M51.9 126h3.6M144.3 120.7h3.6M144.3 122.4h3.6M144.3 124.2h3.6"/>
<path d="M144.3 126h3.6M164.2 121.6h.9M164.6 121.1v.9M164.6 122.4v1.8M182.4 120.7h3.5M182.4 122.4h3.5M182.4 124.2h3.5M182.4 126h3.5M205.5 120.7h3.5M205.5 122.4h3.5M205.5 124.2h3.5M205.5 126h3.5"/>
<path d="M237.5 136.7v1.8M237.5 139.2v2.8M239.3 133.1h1.7l.2-.7 .5 1.4 .4-1.4 .4 1.4 .5-1.4 .4 1.4 .5-1.4 .4 1.4 .3-.7h1.8M249 133.1h12.5M249 136.7h12.5M255.3 133.1v.9l-.9 1.4M255.3 135.8v.9M264.2 120.7v1.7M264.2 124.2v1.8l.7 .2-1.5 .4 1.5 .5-1.5 .4 1.5 .5-1.5 .4 1.5 .5-1.5 .4 .8 .3v1.7M237.5 145.6v1.7M263.7 151.8h.9M264.2 142v1.8"/>
<path d="M264.2 151.3v.9M264.2 152.7v1.8M264.2 156.2v1.8l.7 .2-1.5 .4 1.5 .5-1.5 .4 1.5 .5-1.5 .4 1.5 .4-1.5 .5 .8 .3v1.7M237.5 168.7v1.8M237.5 171.2v2.8M237.5 177.5v1.8M239.3 165.1h1.7l.2-.7 .5 1.4 .4-1.4 .4 1.4 .5-1.4 .4 1.4 .5-1.4 .4 1.4 .3-.7h1.8M249 165.1h12.5M249 168.7h12.5M255.3 165.1v.9l-.9 1.4M255.3 167.8v.9M264.2 174v1.8"/>
</g>
<g fill="none" stroke="#800000" stroke-width=".19">
<path d="M167.3 31.8h14.2v12.4h-14.2zM189.5 39.8h3.6M189.5 38.5a2.84 2.84 0 0 0 3.5 0M38.3 49.6h1.8l-.9 .9zM86.4 42.4h1.7l-.9 .9zM93.2 49.6h1.7l-.9 .9zM142.6 42.4h1.8l-.9 .9zM190.4 48.7h1.8l-.9 .9zM252.6 48.7h1.8l-.9 .9zM38.7 79.8h1.7l-.8 .9zM86.9 72.6h1.7l-.8 .9zM93.5 79.8h1.8l-.9 .9z"/>
<path d="M143.1 72.6h1.8l-.9 .9zM151.3 68.2h1.8l-.9 .9zM159.3 63.8h11.5v3.6h-11.5zM188.9 63.2l.6-.3h2.7a1.81 1.81 0 0 1 1.8 1.8v8a2.67 2.67 0 0 1-2.7 2.7l-2-.1a.83 .83 0 0 1-.7-.8v-10.7zM190.4 64.7h.9l.9 .9v7.1l-.9 .9h-.9zM198.4 67.4h3.5M198.4 68.6a2.84 2.84 0 0 1 3.5 0M199.3 78h1.7l-.8 .9zM226.8 74.5h1.8l-.9 .9zM185.9 86.9h19.6v40.9h-19.6zM34.8 108.2h1.8l-.9 .9zM35.7 101.1h1.8l-.9 .9z"/>
<path d="M235.7 108.2h3.6M235.8 109.5a2.73 2.73 0 0 1 3.4 0M236.6 117.1h1.8l-.9 .9zM251.7 101.1h7.1v7.1h-7.1zM263.3 113.6h1.7l-.8 .8zM160.2 120.7h1.7l-.8 .9zM235.7 138.5h3.6M235.8 139.7a2.81 2.81 0 0 1 3.4 0M251.7 131.3h7.1v7.2h-7.1zM236.6 147.3h1.8l-.9 .9zM263.3 143.8h1.7l-.8 .9zM235.7 170.5h3.6"/>
<path d="M235.8 171.7a2.81 2.81 0 0 1 3.4 0M236.6 179.3h1.8l-.9 .9zM251.7 163.3h7.1v7.2h-7.1zM263.3 175.8h1.7l-.8 .9z"/>
</g>
<g fill="#800000" stroke="#800000" stroke-width=".15">
<path d="M199.3 58.8a.98 .98 0 0 1 1.6 0 .98 .98 0 0 1-.4 1.5 .98 .98 0 0 1-1.3-.9h.2a.8 .8 0 0 1 1.1-.7 .8 .8 0 0 1 .2 1.3 .8 .8 0 0 1-1.3-.4v-.2h-.2z" fill-rule="evenodd"/>
<path d="M84.4 62.2a.98 .98 0 0 1 1.5 .4 .98 .98 0 0 1-.7 1.3 .98 .98 0 0 1-1.1-.9h.1a.8 .8 0 0 1 1.2-.7 .8 .8 0 0 1 .1 1.3 .8 .8 0 0 1-1.2-.4l-.1-.2h-.1v-.3z" fill-rule="evenodd"/>
<path d="M84.4 72.9a.98 .98 0 0 1 1.5 .3 .98 .98 0 0 1-.6 1.4 .98 .98 0 0 1-1.2-1h.1a.8 .8 0 0 1 1.2-.6 .8 .8 0 0 1 .1 1.3 .8 .8 0 0 1-1.2-.4l-.1-.3h-.1v-.3z" fill-rule="evenodd"/>
<path d="M139.3 62.2a.98 .98 0 0 1 1.5 .3 .98 .98 0 0 1-.7 1.4 .98 .98 0 0 1-1.2-.9h.2a.8 .8 0 0 1 1.1-.8 .8 .8 0 0 1 .2 1.3 .8 .8 0 0 1-1.3-.3v-.2h-.2l.1-.3z" fill-rule="evenodd"/>
<path d="M139.3 72.9a.98 .98 0 0 1 1.5 .3 .98 .98 0 0 1-.7 1.4 .98 .98 0 0 1-1.2-1h.2a.8 .8 0 0 1 1.1-.7 .8 .8 0 0 1 .2 1.3 .8 .8 0 0 1-1.3-.3v-.3h-.2l.1-.3z" fill-rule="evenodd"/>
<path d="M84 32a.97 .97 0 0 1 1.5 .3 .97 .97 0 0 1-.6 1.4 .97 .97 0 0 1-1.2-1h.1a.8 .8 0 0 1 1.1-.7 .8 .8 0 0 1 .3 1.3 .8 .8 0 0 1-1.3-.3l-.1-.3h-.1l.1-.5z" fill-rule="evenodd"/>
<path d="M84 42.7a.97 .97 0 0 1 1.5 .3 .97 .97 0 0 1-.6 1.4 .97 .97 0 0 1-1.2-1h.1a.8 .8 0 0 1 1.1-.7 .8 .8 0 0 1 .3 1.3 .8 .8 0 0 1-1.3-.4l-.1-.2h-.1v-.3z" fill-rule="evenodd"/>
<path d="M138.7 32.2a.98 .98 0 0 1 1.6 0 .98 .98 0 0 1-.5 1.5 .98 .98 0 0 1-1.3-1h.2a.8 .8 0 0 1 1.2-.6 .8 .8 0 0 1 .1 1.3 .8 .8 0 0 1-1.3-.4v-.3h-.2z" fill-rule="evenodd"/>
<path d="M138.7 42.9a.98 .98 0 0 1 1.6-.1 .98 .98 0 0 1-.5 1.5 .98 .98 0 0 1-1.3-.9h.2a.8 .8 0 0 1 1.2-.7 .8 .8 0 0 1 .1 1.4 .8 .8 0 0 1-1.3-.5v-.2h-.2z" fill-rule="evenodd"/>
<path d="M164 120.8a.97 .97 0 0 1 1.5 .3 .97 .97 0 0 1-.7 1.4 .97 .97 0 0 1-1.2-.9h.2a.8 .8 0 0 1 1.1-.8 .8 .8 0 0 1 .2 1.3 .8 .8 0 0 1-1.2-.3l-.1-.2h-.2l.2-.6z" fill-rule="evenodd"/>
<path d="M165.8 90.6a.97 .97 0 0 1 1.5 .3 .97 .97 0 0 1-.7 1.4 .97 .97 0 0 1-1.2-.9h.2a.8 .8 0 0 1 1.1-.8 .8 .8 0 0 1 .2 1.3 .8 .8 0 0 1-1.3-.3v-.2h-.2l.1-.3z" fill-rule="evenodd"/>
<path d="M151.6 57.7a.98 .98 0 0 1 1.5 .3 .98 .98 0 0 1-.7 1.4 .98 .98 0 0 1-1.2-.9h.2a.8 .8 0 0 1 1.1-.8 .8 .8 0 0 1 .2 1.3 .8 .8 0 0 1-1.3-.3v-.2h-.2l.2-.6z" fill-rule="evenodd"/>
<path d="M227.1 62.1a.98 .98 0 0 1 1.5 .4 .98 .98 0 0 1-.7 1.4 .98 .98 0 0 1-1.2-1h.2a.81 .81 0 0 1 1.1-.8 .81 .81 0 0 1 .3 1.4 .81 .81 0 0 1-1.4-.4v-.2h-.2l.1-.3z" fill-rule="evenodd"/>
<path d="M199.3 49a.98 .98 0 0 1 1.6 0 .98 .98 0 0 1-.4 1.5 .98 .98 0 0 1-1.3-.9h.2a.8 .8 0 0 1 1.1-.7 .8 .8 0 0 1 .2 1.3 .8 .8 0 0 1-1.3-.4v-.2h-.2z" fill-rule="evenodd"/>
<path d="M28.9 101.2a.98 .98 0 0 1 1.5 .4 .98 .98 0 0 1-.6 1.4 .98 .98 0 0 1-1.3-1h.2a.8 .8 0 0 1 1.1-.7 .8 .8 0 0 1 .2 1.3 .8 .8 0 0 1-1.3-.3v-.3h-.2l.1-.3z" fill-rule="evenodd"/>
<path d="M252.9 31.9a.98 .98 0 0 1 1.5 .3 .98 .98 0 0 1-.7 1.4 .98 .98 0 0 1-1.2-.9h.2a.8 .8 0 0 1 1.1-.8 .8 .8 0 0 1 .2 1.4 .8 .8 0 0 1-1.3-.4v-.2h-.2l.1-.3z" fill-rule="evenodd"/>
<path d="M263.5 88.8a.98 .98 0 0 1 1.5 .3 .98 .98 0 0 1-.6 1.4 .98 .98 0 0 1-1.2-.9h.2a.8 .8 0 0 1 1.1-.8 .8 .8 0 0 1 .2 1.3 .8 .8 0 0 1-1.3-.3v-.2h-.2v-.3z" fill-rule="evenodd"/>
<path d="M263.5 119a.98 .98 0 0 1 1.5 .3 .98 .98 0 0 1-.6 1.4 .98 .98 0 0 1-1.2-.9h.2a.8 .8 0 0 1 1.1-.8 .8 .8 0 0 1 .2 1.3 .8 .8 0 0 1-1.3-.3v-.2h-.2l.2-.6z" fill-rule="evenodd"/>
<path d="M263.5 151a.98 .98 0 0 1 1.5 .3 .98 .98 0 0 1-.6 1.4 .98 .98 0 0 1-1.2-.9h.2a.8 .8 0 0 1 1.1-.8 .8 .8 0 0 1 .2 1.3 .8 .8 0 0 1-1.3-.3v-.2h-.2v-.3z" fill-rule="evenodd"/>
<circle cx="254.4" cy="105.2" r=".11"/>
<circle cx="255.3" cy="105.6" r=".11"/>
<circle cx="254.4" cy="135.4" r=".11"/>
<circle cx="255.3" cy="135.8" r=".11"/>
<circle cx="254.4" cy="167.4" r=".11"/>
<circle cx="255.3" cy="167.8" r=".11"/>
</g>
<path d="M217 65.6h5.4v7.1h-5.4z" fill="none" stroke="#800000" stroke-width=".3"/>
<path d="M217.9 70.9h.9M217.9 69.1h.9M217.9 67.4h.9M220.6 70.9h.9M220.6 69.1h.9M220.6 67.4h.9" fill="none" stroke="#800000" stroke-width=".44"/>
<g fill="none" stroke="#008000" stroke-width=".15">
<path d="M38.4 38.9l6.1 .1M38.4 35.3l6.1 .1M38.4 37.1l6.1 .1M69.4 35.4h15.2M69.4 39h8.9M91.7 38.9l7.7 .1M91.7 35.3l7.7 .1M91.7 37.1l7.7 .1M124.2 35.4h15.3M124.2 39h8.9M155.7 35.3h8M191.3 36.2h3.5v2.7h10.7"/>
<path d="M253.5 35.3v3.6h-16M38.4 46l6.1 .1M38.4 42.5h6.1M38.4 44.2l6.1 .1M38.4 40.7h6.1M39.2 47.9h5.3M69.4 46.1h15.2M69.4 42.5h8.9M69.4 44.3h8.9M87.2 40.6l-17.8 .1M91.7 46l7.7 .1M91.7 42.5h7.7"/>
<path d="M91.7 44.2l7.7 .1M91.7 40.7h7.7M94 47.9h5.4M124.2 46.1h15.3M124.2 42.5h8.9M124.2 44.3h8.9M143.5 40.6l-19.3 .1M155.7 40.7h8M191.3 44.2h14.2M191.3 41.6v5.3M196.6 42.5h8.9M196.6 40.7h8.9"/>
<path d="M205.5 46h-3.6v6.2h-1.7M237.5 42.5h16v4.4M237.5 44.2h8.9M237.5 40.7h8.9M38.4 65.6h6.5M38.4 67.4h6.5M38.4 72.7h6.5M38.4 70.9l6.5 .1M38.4 69.1l6.5 .1M38.4 74.5h6.5M38.4 76.2l6.5 .1M39.6 78.1h5.3"/>
<path d="M69.8 65.6h15.2M69.8 76.3h15.2M69.8 69.2h8.9M69.8 72.7h8.9M69.8 74.5h8.9M87.8 70.8l-18 .2M93.5 65.6h6.3M93.5 67.4h6.3M93.5 72.7h6.3M93.5 70.9l6.3 .1M93.5 69.1l6.3 .1M93.5 74.5h6.3"/>
<path d="M93.5 76.2l6.3 .1M94.4 78.1h5.4M124.7 65.6h15.2M124.7 76.3h15.2M124.7 69.2h8.8M124.7 72.7h8.8M124.7 74.5h8.8M144 70.8l-19.3 .2M152.2 61.1v3.6h3.5M152.2 66.5h3.5M174.4 65.6h8M194.8 72.7h5.4"/>
<path d="M200.2 62v3.6h-5.4M200.2 70.9v5.3M208.2 67.4h6.2M208.2 70.9h6.2M208.2 69.1h6.2M225 70.9h2.7v1.8M225 69.1h6.3M227.7 65.6v1.8h-2.7M36.6 99.4v-3.6h1.8v7.1h13.5M40.2 99.4h11.7M147.9 99.4h9.6M166.4 94v1.8"/>
<path d="M173.5 88.7h8.9M209 97.6h10.7M264.2 92.2v1.8M29.5 104.7h22.4M33.1 104.7v6.2h6.2v-2.7h12.6M35.7 106.4h16.2M40.2 117.1h11.7M40.2 118.9h11.7M40.2 113.6h11.7M40.2 101.1h11.7M40.2 111.8h11.7M40.2 115.3h11.7"/>
<path d="M120.3 103.3h5.9M147.9 104.7h18.5M147.9 108.2h9.4M147.9 118.9l13.2-.1v.1M147.9 102.9h9.6M147.9 106.4h9.4M147.9 113.6h9.6M147.9 101.1h9.6M147.9 110h9.6M147.9 111.8h9.6M166.4 102.9v3.5h7.1M175.3 104.7h7.1"/>
<path d="M175.3 108.2h7.1M175.3 102.9h7.1M175.3 106.4h7.1M175.3 117.1h7.1M175.3 118.9h7.1M175.3 101.1h7.1M175.3 110h7.1M175.3 111.8h7.1M175.3 115.3h7.1M209 104.7h10.7M209 108.2h10.7M209 102.9h10.7"/>
<path d="M209 106.4h10.7M209 117.1h10.7M209 118.9h10.7M209 101.1h10.7M209 110h10.7M209 111.8h10.7M209 115.3h10.7M226.8 102.9h12.5M237.5 102.9v3.5M237.5 111.8v3.5M246.4 102.9h2.6M261.5 102.9h2.7"/>
<path d="M261.5 106.4h2.7M264.2 101.1v10.7M40.2 120.7h11.7M40.2 122.4h11.7M46 124.2h6M46 126h6M147.9 124.2h16.7M147.9 126h6.6M175.3 124.2h7.1M175.3 120.7h7.1M175.3 122.4h7.1M175.3 126h7.1"/>
<path d="M209 124.2h10.7M209 120.7h10.7M209 122.4h10.7M209 126h10.7M226.8 133.1h12.5M237.5 133.1v3.6M246.4 133.1h2.6M261.5 136.7h2.7M261.5 133.1h2.7M264.2 122.4v1.8M264.2 131.3v10.7M237.5 142v3.6"/>
<path d="M264.2 154.5v1.7M226.8 165.1h12.5M237.5 165.1v3.6M237.5 174v3.5M246.4 165.1h2.6M261.5 168.7h2.7M261.5 165.1h2.7M264.2 163.3v10.7"/>
</g>
<g fill="#008000" stroke="#008000" stroke-width=".15">
<circle cx="200.2" cy="65.6" r=".36"/>
<circle cx="33.1" cy="104.7" r=".36"/>
<circle cx="200.2" cy="72.7" r=".36"/>
<circle cx="191.3" cy="44.2" r=".36"/>
<circle cx="264.2" cy="106.4" r=".36"/>
<circle cx="264.2" cy="102.9" r=".36"/>
<circle cx="264.2" cy="136.7" r=".36"/>
<circle cx="264.2" cy="133.1" r=".36"/>
<circle cx="264.2" cy="168.7" r=".36"/>
<circle cx="264.2" cy="165.1" r=".36"/>
<circle cx="166.4" cy="104.7" r=".36"/>
<circle cx="237.5" cy="133.1" r=".36"/>
<circle cx="237.5" cy="165.1" r=".36"/>
<circle cx="237.5" cy="102.9" r=".36"/>
</g>
<use href="#words"/>
</svg>
